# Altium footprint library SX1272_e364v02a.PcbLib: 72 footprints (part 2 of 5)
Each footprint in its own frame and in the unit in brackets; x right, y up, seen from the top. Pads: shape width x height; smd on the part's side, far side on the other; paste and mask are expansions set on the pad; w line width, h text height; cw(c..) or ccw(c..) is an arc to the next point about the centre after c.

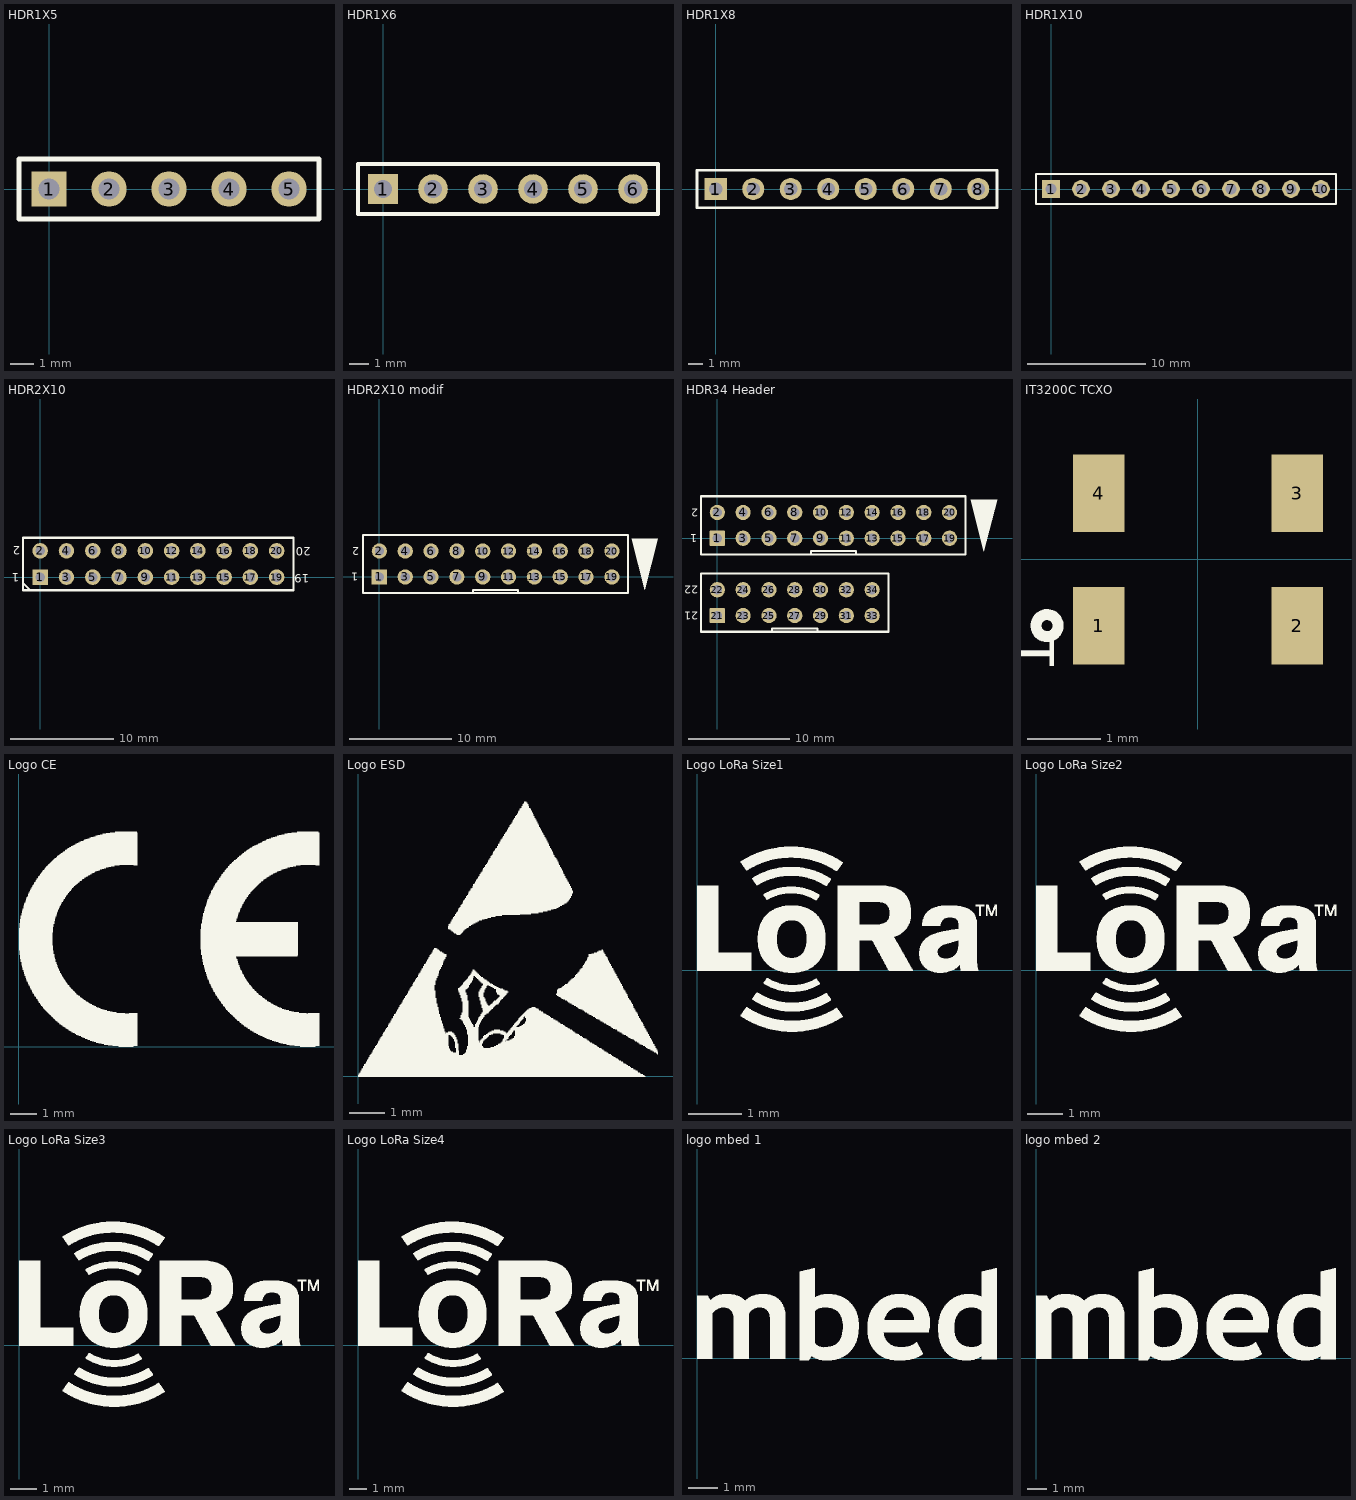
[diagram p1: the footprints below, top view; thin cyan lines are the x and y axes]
## HDR1X5 [mm] "Connector; Header; 5 Position"
pads (5):
  rect 1.5x1.5 hole 0.9: 1(0,0)
  round 1.5 hole 0.9: 2(2.54,0) 3(5.08,0) 4(7.62,0) 5(10.16,0)
Top Overlay:
  lines w0.2: -1.27,-1.27 -1.27,1.27 11.43,1.27 11.43,-1.27 -1.27,-1.27

## HDR1X6 [mm] "Connector; Header; 6 Position"
pads (6):
  rect 1.5x1.5 hole 0.9: 1(0,0)
  round 1.5 hole 0.9: 2(2.54,0) 3(5.08,0) 4(7.62,0) 5(10.16,0) 6(12.7,0)
Top Overlay:
  lines w0.2: -1.27,-1.27 -1.27,1.27 13.97,1.27 13.97,-1.27 -1.27,-1.27

## HDR1X8 [mm] "Connector; Header; 8 Position"
pads (8):
  rect 1.5x1.5 hole 0.9: 1(0,0)
  round 1.5 hole 0.9: 2(2.54,0) 3(5.08,0) 4(7.62,0) 5(10.16,0) 6(12.7,0) 7(15.24,0) 8(17.78,0)
Top Overlay:
  lines w0.2: -1.27,-1.27 19.05,-1.27 19.05,1.27 -1.27,1.27 -1.27,-1.27

## HDR1X10 [mm] "Connector; Header; 10 Position"
pads (10):
  rect 1.5x1.5 hole 0.9: 1(0,0)
  round 1.5 hole 0.9: 2(2.54,0) 3(5.08,0) 4(7.62,0) 5(10.16,0) 6(12.7,0) 7(15.24,0) 8(17.78,0) 9(20.32,0) 10(22.86,0)
Top Overlay:
  lines w0.2: -1.27,-1.27 24.13,-1.27 24.13,1.27 0.635,1.27 -1.27,1.27 -1.27,-1.27

## HDR2X10 [mm] "Connector; Header; 10x2 Position"
pads (20):
  rect 1.5x1.5 hole 0.9 paste+0 mask+0.1: 1(0,0)
  round 1.5 hole 0.9 paste+0 mask+0.1: 2(0,2.54) 3(2.54,0) 4(2.54,2.54) 5(5.08,0) 6(5.08,2.54) 7(7.62,0) 8(7.62,2.54) 9(10.16,0) 10(10.16,2.54) 11(12.7,0) 12(12.7,2.54) 13(15.24,0) 14(15.24,2.54) 15(17.78,0) 16(17.78,2.54) 17(20.32,0) 18(20.32,2.54) 19(22.86,0) 20(22.86,2.54)
Top Overlay:
  lines w0.2: -1.65,-0.6 -1.015,-1.235 ; -1.65,-1.27 0.635,-1.27 24.5,-1.27 24.5,3.81 0.635,3.81 -1.65,3.81 -1.65,-1.27
  text "20" at 26.15,2.9 h0.8
  text "19" at 26,0.3 h0.8
  text "1" at -2.05,0.4 h0.8
  text "2" at -1.95,3 h0.8

## HDR2X10 modif [mm] "Connector; Header; 10x2 Position - modified"
pads (20):
  rect 1.5x1.5 hole 0.9: 1(0,0)
  round 1.5 hole 0.9: 2(0,2.54) 3(2.54,0) 4(2.54,2.54) 5(5.08,0) 6(5.08,2.54) 7(7.62,0) 8(7.62,2.54) 9(10.16,0) 10(10.16,2.54) 11(12.7,0) 12(12.7,2.54) 13(15.24,0) 14(15.24,2.54) 15(17.78,0) 16(17.78,2.54) 17(20.32,0) 18(20.32,2.54) 19(22.86,0) 20(22.86,2.54)
Top Overlay:
  region: 26.107,-1.275 27.394,3.775 24.82,3.775
  lines w0.2: 9.207,-1.587 9.207,-1.27 13.335,-1.27 13.652,-1.27 13.652,-1.587 ; -1.587,-1.587 -1.587,4.127 24.447,4.127 24.447,-1.587 -1.587,-1.587
  text "1" at -2.1,0.4 h0.8
  text "2" at -2,2.9 h0.8

## HDR34 Header [mm] "Connector; Header; 34 Position - SM12xx Header"
pads (34):
  rrect10% 1.5x1.5 hole 0.9 mask+0.05: 1(0,0) 21(0,-7.62)
  round 1.5 hole 0.9 mask+0.05: 2(0,2.54) 3(2.54,0) 4(2.54,2.54) 5(5.08,0) 6(5.08,2.54) 7(7.62,0) 8(7.62,2.54) 9(10.16,0) 10(10.16,2.54) 11(12.7,0) 12(12.7,2.54) 13(15.24,0) 14(15.24,2.54) 15(17.78,0) 16(17.78,2.54) 17(20.32,0) 18(20.32,2.54) 19(22.86,0) 20(22.86,2.54) 22(0,-5.08) 23(2.54,-7.62) 24(2.54,-5.08) 25(5.08,-7.62) 26(5.08,-5.08) 27(7.62,-7.62) 28(7.62,-5.08) 29(10.16,-7.62) 30(10.16,-5.08) 31(12.7,-7.62) 32(12.7,-5.08) 33(15.24,-7.62) 34(15.24,-5.08)
Top Overlay:
  region: 26.243,-1.275 27.53,3.775 24.956,3.775
  lines w0.2: 5.397,-9.207 5.397,-8.89 9.525,-8.89 9.842,-8.89 9.842,-9.207 ; 9.207,-1.587 9.207,-1.27 13.335,-1.27 13.652,-1.27 13.652,-1.587 ; -1.587,-9.207 -1.587,-3.492 16.828,-3.492 16.828,-9.207 -1.587,-9.207 ; -1.587,-1.587 24.447,-1.587 24.447,4.127 -1.587,4.127 -1.587,-1.587
  text "2" at -1.9,2.9 h0.8
  text "1" at -2,0.4 h0.8
  text "21" at -1.9,-7.25 h0.8
  text "22" at -1.9,-4.7 h0.8

## IT3200C TCXO [mm] "SMD 3.2x2.5mm for IT3200C TCXO"
height 1
pads (4):
  rect 0.7x1.05 smd mask+0.05: 1(-1.35,-0.9) 2(1.35,-0.9) 3(1.35,0.9) 4(-1.35,0.9)
Top Overlay:
  circle w0.15: c-2.05,-0.9 r0.15
  text "1" at -1.95,-1.55 h0.6
3D body: height 1, standoff 0, extent -1.6,-1.25 1.6,1.25

## Logo CE [mm] "Logo CE"
height 0.1
Top Overlay:
  drawing of 654 lines, arcs and shapes, not listed

## Logo ESD [mm] "Logo ESD"
height 0.1
Top Overlay:
  drawing of 682 lines, arcs and shapes, not listed

## Logo LoRa Size1 [mm] "Logo LoRa Size1 - Top Overlay"
Top Overlay:
  drawing of 2375 lines, arcs and shapes, not listed

## Logo LoRa Size2 [mm] "Logo LoRa Size2 - Top Overlay"
Top Overlay:
  drawing of 2374 lines, arcs and shapes, not listed

## Logo LoRa Size3 [mm] "Logo LoRa Size3 - Top Overlay"
Top Overlay:
  drawing of 2375 lines, arcs and shapes, not listed

## Logo LoRa Size4 [mm] "Logo LoRa Size4 - Top Overlay"
Top Overlay:
  drawing of 2375 lines, arcs and shapes, not listed

## logo mbed 1 [mm] "logo mbed 1"
height 0.2
Top Overlay:
  drawing of 1792 lines, arcs and shapes, not listed

## logo mbed 2 [mm] "logo mbed 2"
height 0.2
Top Overlay:
  drawing of 1792 lines, arcs and shapes, not listed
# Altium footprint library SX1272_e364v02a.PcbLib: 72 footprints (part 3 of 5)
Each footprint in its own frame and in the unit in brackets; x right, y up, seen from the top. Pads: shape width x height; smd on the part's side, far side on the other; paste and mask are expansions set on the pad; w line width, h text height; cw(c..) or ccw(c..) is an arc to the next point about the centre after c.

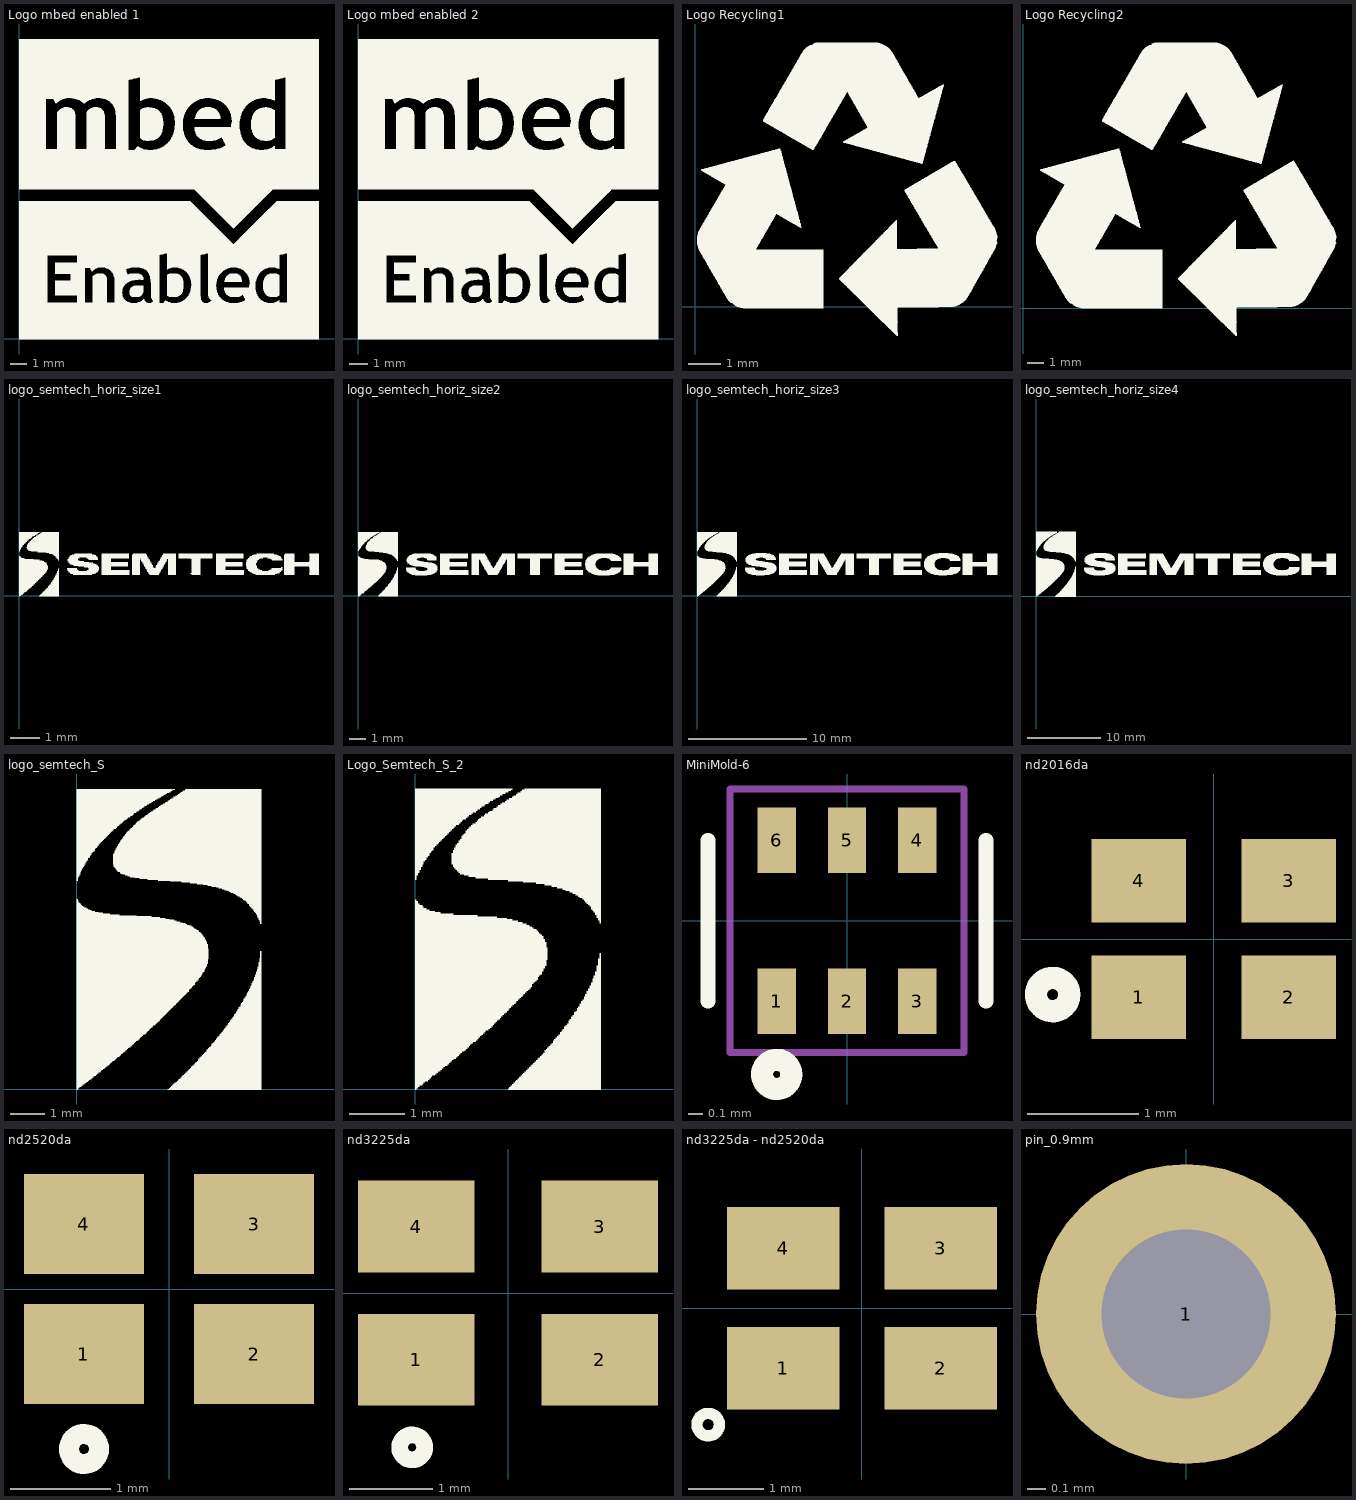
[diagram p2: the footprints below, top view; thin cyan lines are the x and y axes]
## Logo mbed enabled 1 [mm] "Logo mbed enabled 1"
height 0.2
Top Overlay:
  drawing of 3679 lines, arcs and shapes, not listed

## Logo mbed enabled 2 [mm] "Logo mbed enabled 2"
Top Overlay:
  drawing of 3679 lines, arcs and shapes, not listed

## Logo Recycling1 [mm] "Logo Recycling1"
height 0.1
Top Overlay:
  drawing of 3302 lines, arcs and shapes, not listed

## Logo Recycling2 [mm] "Logo Recycling2"
height 0.1
Top Overlay:
  drawing of 3309 lines, arcs and shapes, not listed

## logo_semtech_horiz_size1 [mm] "Logo semtech horizontal - size1 - S"
Top Overlay:
  drawing of 453 lines, arcs and shapes, not listed

## logo_semtech_horiz_size2 [mm] "Logo semtech horizontal - size2 - M"
Top Overlay:
  drawing of 790 lines, arcs and shapes, not listed

## logo_semtech_horiz_size3 [mm] "Logo semtech horizontal - size3 - L"
Top Overlay:
  drawing of 1137 lines, arcs and shapes, not listed

## logo_semtech_horiz_size4 [mm] "Logo semtech horizontal - size4 - XL"
Top Overlay:
  drawing of 1852 lines, arcs and shapes, not listed

## logo_semtech_S [mm] "Logo semtech S size4 - XL"
Top Overlay:
  drawing of 642 lines, arcs and shapes, not listed

## Logo_Semtech_S_2 [mm] "Logo semtech S - size2"
Top Overlay:
  drawing of 393 lines, arcs and shapes, not listed

## MiniMold-6 [mm] "MiniMold-6 Package 1.5x1.1mm"
height 0.55
pads (6):
  rect 0.26x0.45 smd mask+0.05: 1(-0.48,-0.55) 2(0,-0.55) 3(0.48,-0.55) 4(0.48,0.55) 5(0,0.55) 6(-0.48,0.55)
Top Overlay:
  circle w0.15: c-0.48,-1.05 r0.1
  lines w0.1: -0.95,-0.55 -0.95,0.55 ; 0.95,-0.55 0.95,0.55
Mechanical 15:
  lines w0.05: -0.8,-0.9 0.8,-0.9 0.8,0.9 -0.8,0.9 -0.8,-0.9
3D body: height 1, standoff 0, extent -0.75,-0.55 0.75,0.55

## nd2016da [mm] "Crystal SMD 2.0x1.6mm"
height 0.55
pads (4):
  rect 0.85x0.75 smd mask+0.05: 1(-0.675,-0.525) 2(0.675,-0.525) 3(0.675,0.525) 4(-0.675,0.525)
Top Overlay:
  circle w0.2: c-1.45,-0.5 r0.15
3D body: height 1, standoff 0, extent -1,-0.8 1,0.8

## nd2520da [mm] "Crystal SMD 2.5x2.0mm"
height 0.7
pads (4):
  rect 1.2x1 smd mask+0.05: 1(-0.85,-0.65) 2(0.85,-0.65) 3(0.85,0.65) 4(-0.85,0.65)
Top Overlay:
  circle w0.2: c-0.85,-1.6 r0.15
3D body: height 1, standoff 0, extent -1.25,-1 1.25,1

## nd3225da [mm] "Crystal SMD 3.2x2.5mm"
height 0.8
pads (4):
  rect 1.4x1.1 smd mask+0.05: 1(-1.1,-0.8) 2(1.1,-0.8) 3(1.1,0.8) 4(-1.1,0.8)
Top Overlay:
  circle w0.2: c-1.15,-1.85 r0.15
3D body: height 1, standoff 0, extent -1.6,-1.25 1.6,1.25

## nd3225da - nd2520da [mm] "Crystal SMD 3.2x2.5mm compatible with 2.5x2.0mm"
height 0.8
pads (4):
  rect 1.5x1.1 smd mask+0.05: 1(-1.05,-0.8) 2(1.05,-0.8) 3(1.05,0.8) 4(-1.05,0.8)
Top Overlay:
  circle w0.15: c-2.05,-1.55 r0.15
3D body: height 1, standoff 0, extent -1.6,-1.25 1.6,1.25

## pin_0.9mm [mm] "Generic Pin 0.9mm; 1 Lead"
height 1
pads (1):
  round 1.6 hole 0.9 mask+0.05: 1(0,0)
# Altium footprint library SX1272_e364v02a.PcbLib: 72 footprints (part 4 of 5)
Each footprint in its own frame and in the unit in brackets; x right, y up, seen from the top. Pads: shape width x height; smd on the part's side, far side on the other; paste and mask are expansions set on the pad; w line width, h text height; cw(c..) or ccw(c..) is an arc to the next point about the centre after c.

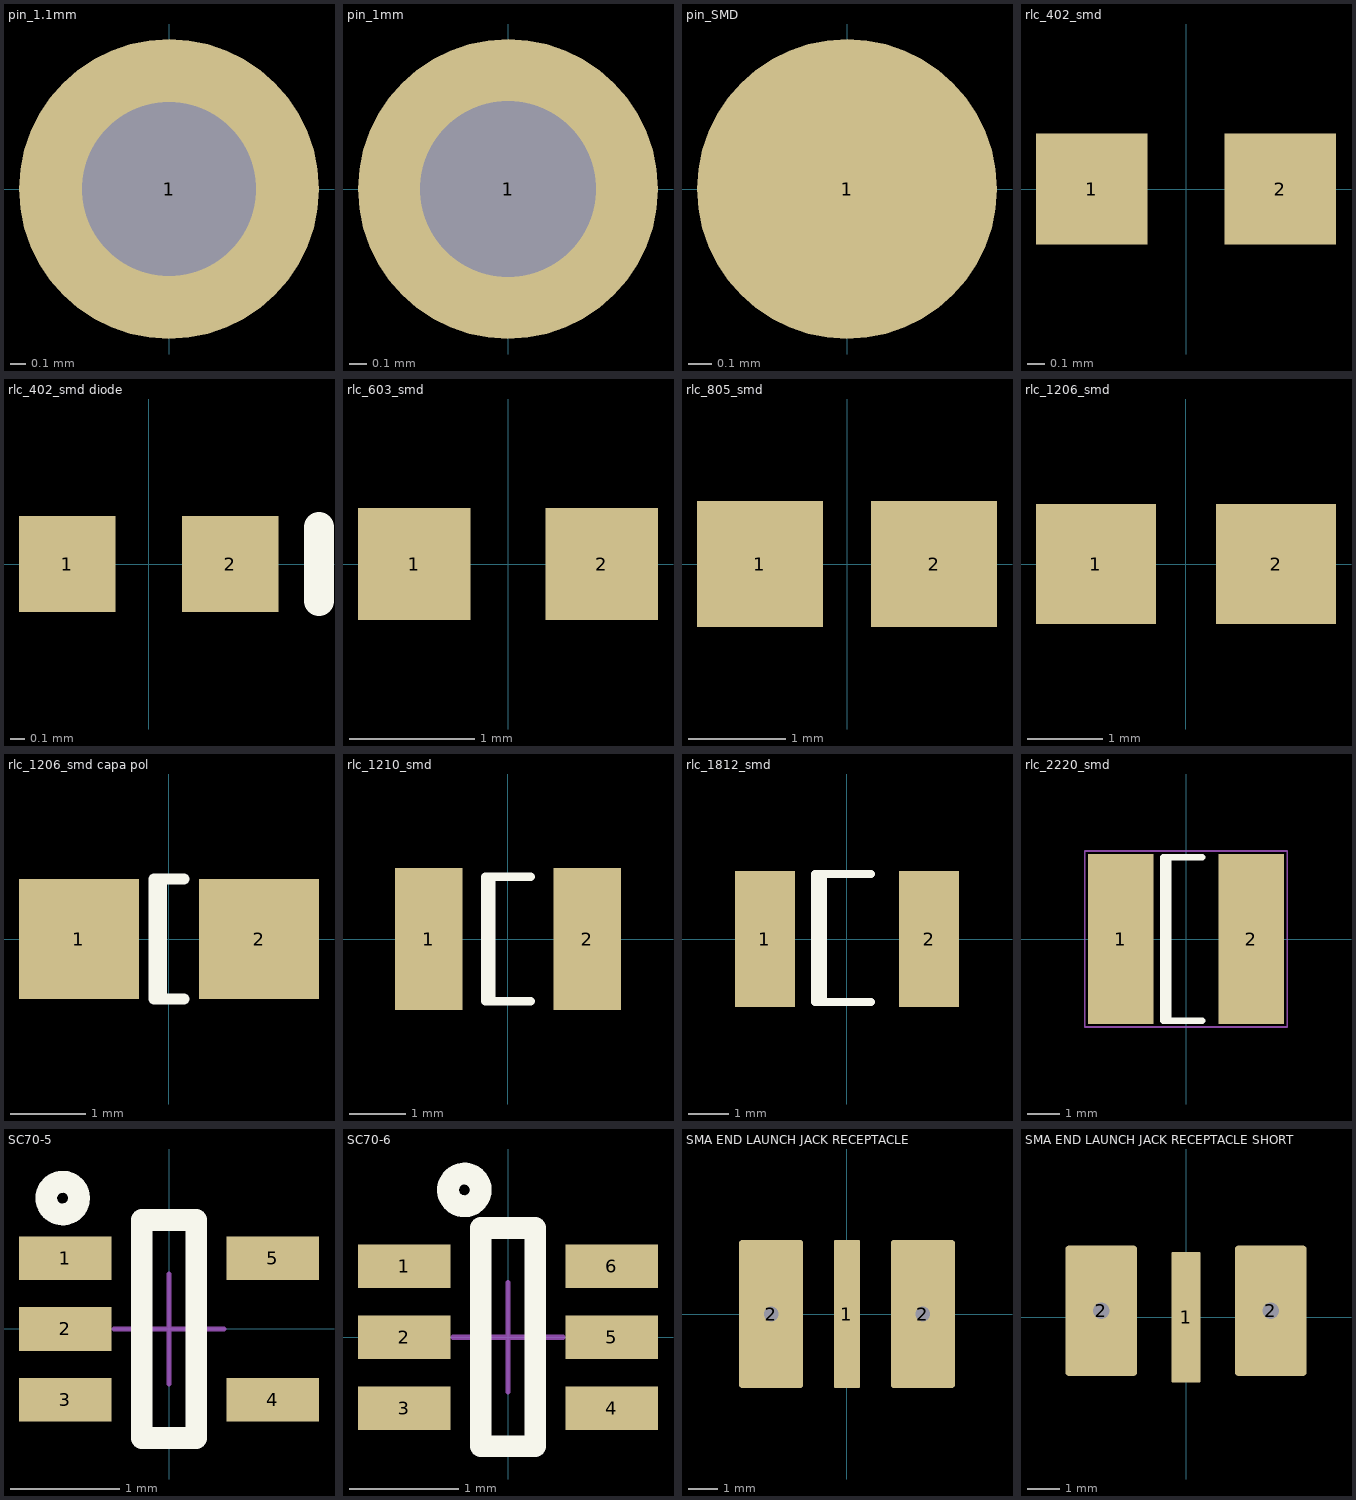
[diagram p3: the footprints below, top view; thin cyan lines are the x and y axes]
## pin_1.1mm [mm] "Generic Pin 1.1mm; 1 Lead"
height 1
pads (1):
  round 1.9 hole 1.1 mask+0.05: 1(0,0)

## pin_1mm [mm] "Generic Pin 1.1mm; 1 Lead"
height 1
pads (1):
  round 1.7 hole 1 paste+0 mask+0.05: 1(0,0)

## pin_SMD [mm] "Generic Pin; 1 pin SMD"
height 0.5
pads (1):
  round 1.27 smd paste-1 mask+0.05: 1(0,0)

## rlc_402_smd [mm] "Chip SMD component 402; Body 1.0 x 0.5 mm (LxW typ)"
height 0.8
pads (2):
  rect 0.65x0.65 smd mask+0.05: 1(-0.55,0) 2(0.55,0)

## rlc_402_smd diode [mm] "Chip SMD component 402; Body 1.0 x 0.5 mm (LxW typ)"
height 0.8
pads (2):
  rect 0.65x0.65 smd mask+0.05: 1(-0.55,0) 2(0.55,0)
Top Overlay:
  lines w0.2: 1.15,-0.25 1.15,0.25

## rlc_603_smd [mm] "Chip SMD component 603; Body 1.6 x 0.8mm (LxW typ)"
height 1
pads (2):
  rect 0.9x0.9 smd paste+0 mask+0.05: 1(-0.75,0) 2(0.75,0)

## rlc_805_smd [mm] "Chip SMD component 805; Body 2.0 x 1.25 mm (LxW typ)"
height 1.4
pads (2):
  rect 1.3x1.3 smd mask+0.05: 1(-0.9,0) 2(0.9,0)

## rlc_1206_smd [mm] "Chip SMD component 1206; Body 3.2 x 1.6 mm (LxW typ)"
height 2
pads (2):
  rect 1.6x1.6 smd mask+0.05: 1(-1.2,0) 2(1.2,0)

## rlc_1206_smd capa pol [mm] "Chip SMD component 1206; Body 3.2 x 1.6 mm (LxW typ)"
height 2
pads (2):
  rect 1.6x1.6 smd mask+0.05: 1(-1.2,0) 2(1.2,0)
Top Overlay:
  lines w0.15: -0.1,-0.8 -0.1,0.8 ; 0.2,-0.8 -0.2,-0.8 -0.2,0.8 0.2,0.8

## rlc_1210_smd [mm] "Chip SMD component 1210; Body 3.2 x 2.5 mm (LxW typ)"
height 2
pads (2):
  rect 1.2x2.5 smd mask+0.05: 1(-1.4,0) 2(1.4,0)
Top Overlay:
  lines w0.15: -0.3,-1.1 -0.3,1.1 ; 0.4,-1.1 -0.4,-1.1 -0.4,1.1 0.4,1.1

## rlc_1812_smd [mm] "Chip SMD component 1812; Body 4.5 x 3.2 mm (LxW typ)"
height 2.5
pads (2):
  rect 1.5x3.4 smd mask+0.05: 1(-2.05,0) 2(2.05,0)
Top Overlay:
  lines w0.2: -0.606,-1.579 -0.606,1.621 ; 0.604,-1.579 -0.796,-1.579 -0.796,1.621 0.604,1.621

## rlc_2220_smd [mm] "Chip SMD component ; Body 5.7 x 5.0 mm (LxW typ)"
height 5
pads (2):
  rect 2x5.2 smd mask+0.05: 1(-2,0) 2(2,0)
Top Overlay:
  lines w0.2: -0.55,-2.5 -0.55,2.5 ; 0.5,-2.5 -0.7,-2.5 -0.7,2.5 0.5,2.5
Mechanical 15:
  lines w0.05: -3.1,-2.7 3.1,-2.7 3.1,2.7 -3.1,2.7 -3.1,-2.7

## SC70-5 [mm] "SC70 5-Leads, Body 2.0x1.25mm, Pitch 0.65mm"
height 1.45
pads (5):
  rect 0.85x0.4 smd mask+0.05: 1(-0.95,0.65) 2(-0.95,0) 3(-0.95,-0.65) 4(0.95,-0.65) 5(0.95,0.65)
Top Overlay:
  circle w0.2: c-0.975,1.2 r0.15
  lines w0.2: -0.25,-1 0.25,-1 0.25,1 -0.25,1 -0.25,-1
Mechanical 15:
  lines w0.05: -0.5,0 0.5,0 ; 0,-0.5 0,0.5
3D body: height 1.45, standoff 0, extent -0.625,-1 0.625,1

## SC70-6 [mm] "SC70 6-Leads, Body 2.0x1.25mm, Pitch 0.65mm"
height 1.45
pads (6):
  rect 0.85x0.4 smd mask+0.05: 1(-0.95,0.65) 2(-0.95,0) 3(-0.95,-0.65) 4(0.95,-0.65) 5(0.95,0) 6(0.95,0.65)
Top Overlay:
  circle w0.2: c-0.4,1.35 r0.15
  lines w0.2: -0.25,-1 0.25,-1 0.25,1 -0.25,1 -0.25,-1
Mechanical 15:
  lines w0.05: -0.5,0 0.5,0 ; 0,-0.5 0,0.5
3D body: height 1.45, standoff 0, extent -0.625,-1 0.625,1

## SMA END LAUNCH JACK RECEPTACLE [mm] "SMA Connector - End Launch Jack Receptacle"
height 8
pads (3):
  rrect10% 0.9x5.08 smd paste+0 mask+0.05: 1(0,0)
  rrect10% 2.2x5.08 hole 0.5 mask+0.05: 2(-2.6,0) 2(2.6,0)

## SMA END LAUNCH JACK RECEPTACLE SHORT [mm] "SMA Connector - End Launch Jack Receptacle - Short"
height 8
pads (3):
  rrect10% 0.9x4 smd paste+0 mask+0.05: 1(0,0)
  rrect10% 2.2x4 hole 0.5 mask+0.05: 2(-2.6,0.2) 2(2.6,0.2)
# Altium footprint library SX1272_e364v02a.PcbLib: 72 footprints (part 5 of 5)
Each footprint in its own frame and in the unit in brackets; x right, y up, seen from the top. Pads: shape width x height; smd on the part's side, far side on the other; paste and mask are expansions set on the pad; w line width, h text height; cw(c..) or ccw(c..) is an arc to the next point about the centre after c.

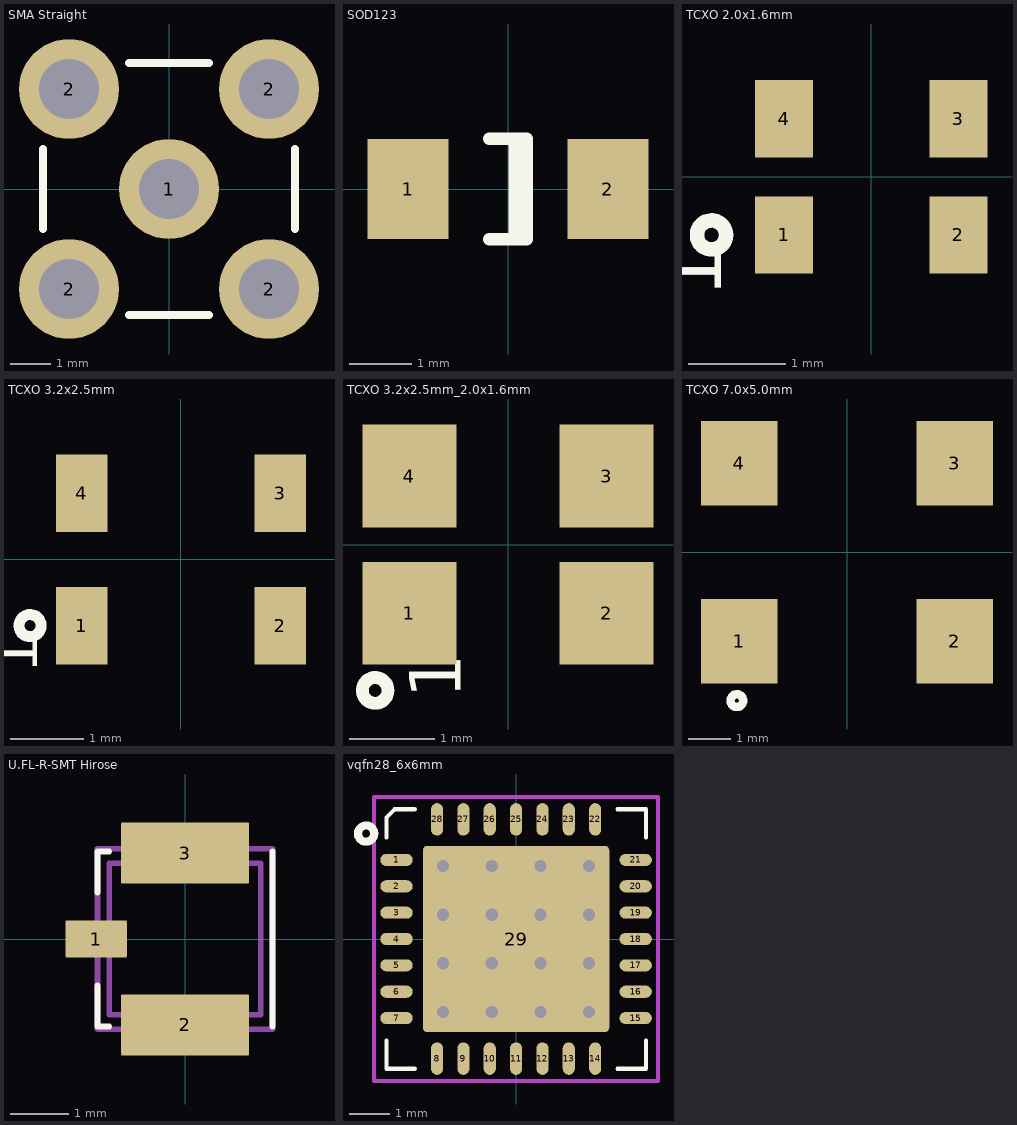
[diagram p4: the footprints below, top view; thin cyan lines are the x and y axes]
## SMA Straight [mm] "SMA Connector; Straight"
height 10
pads (5):
  round 2.5 hole 1.5 paste+0 mask+0.1: 1(0,0) 2(-2.5,-2.5) 2(-2.5,2.5) 2(2.5,-2.5) 2(2.5,2.5)
Top Overlay:
  lines w0.2: -3.15,-1 -3.15,1 ; -1,-3.15 1,-3.15 ; -1,3.15 1,3.15 ; 3.15,-1 3.15,1
Mechanical 1:
  circle w0.025: c0,0 r0.2

## SOD123 [mm] "SOD123; Chip Diode; Body  2.7 x 1.6 mm (LxW typ)"
height 1.35
pads (2):
  rect 1.3x1.6 smd mask+0.05: 1(-1.6,0) 2(1.6,0)
Top Overlay:
  lines w0.2: -0.3,-0.8 0.3,-0.8 0.3,0.8 -0.3,0.8 ; 0.11,-0.8 0.11,0.8

## TCXO 2.0x1.6mm [mm] "SMD 2.0x1.6mm for TCXO or VCTCXO"
height 1
pads (4):
  rect 0.6x0.8 smd mask+0.05: 1(-0.9,-0.6) 2(0.9,-0.6) 3(0.9,0.6) 4(-0.9,0.6)
Top Overlay:
  circle w0.15: c-1.65,-0.6 r0.15
  text "1" at -1.55,-1.25 h0.6
3D body: height 1, standoff 0, extent -1,-0.8 1,0.8

## TCXO 3.2x2.5mm [mm] "SMD 3.2x2.5mm for TCXO or VCTCXO"
height 1
pads (4):
  rect 0.7x1.05 smd mask+0.05: 1(-1.35,-0.9) 2(1.35,-0.9) 3(1.35,0.9) 4(-1.35,0.9)
Top Overlay:
  circle w0.15: c-2.05,-0.9 r0.15
  text "1" at -1.95,-1.55 h0.6
3D body: height 1, standoff 0, extent -1.6,-1.25 1.6,1.25

## TCXO 3.2x2.5mm_2.0x1.6mm [mm] "SMD 3.2x2.5mm & 2.0x1.6mm compatible for TCXO or VCTCXO"
height 1
pads (4):
  rect 1.1x1.2 smd mask+0.05: 1(-1.15,-0.8) 2(1.15,-0.8) 3(1.15,0.8) 4(-1.15,0.8)
Top Overlay:
  circle w0.15: c-1.55,-1.7 r0.15
  text "1" at -0.55,-1.8 h0.6
3D body: height 1, standoff 0, extent -1.6,-1.25 1.6,1.25

## TCXO 7.0x5.0mm [mm] "VTCXO SMD 7.0x5.0mm"
height 1
pads (4):
  rect 1.8x2 smd mask+0.05: 1(-2.54,-2.1) 2(2.54,-2.1) 3(2.54,2.1) 4(-2.54,2.1)
Top Overlay:
  circle w0.2: c-2.6,-3.5 r0.15
3D body: height 1, standoff 0, extent -3.5,-2.5 3.5,2.5

## U.FL-R-SMT Hirose [mm] "Hirose U.FL RF receptacle - U.FL-R-SMT"
height 1.2
pads (3):
  rrect5% 1.05x0.635 smd: 1(-1.525,0)
  rrect5% 2.2x1.05 smd: 2(0,-1.475) 3(0,1.475)
Top Overlay:
  lines w0.1: -1.5,-0.8 -1.5,-1.5 -1.3,-1.5 ; -1.5,0.8 -1.5,1.5 -1.3,1.5 ; 1.5,-1.5 1.5,1.5
Mechanical 13:
  lines w0.1: -1.5,-1.55 1.5,-1.55 1.5,1.55 -1.5,1.55 -1.5,-1.55
Mechanical 15:
  lines w0.1: -1.3,-1.3 1.3,-1.3 1.3,1.3 -1.3,1.3 -1.3,-1.3
3D body: height 16, standoff 1.3, extent -1.5,-1.5 1.5,1.5

## vqfn28_6x6mm [mm] "28 Leads, Body 6.0x6.0mm, Pitch 0.65mm, VQFN28"
height 1
pads (29):
  oval 0.8x0.3 smd mask+0.05: 1(-2.95,1.95) 2(-2.95,1.3) 3(-2.95,0.65) 4(-2.95,0) 5(-2.95,-0.65) 6(-2.95,-1.3) 7(-2.95,-1.95) 15(2.95,-1.95) 16(2.95,-1.3) 17(2.95,-0.65) 18(2.95,0) 19(2.95,0.65) 20(2.95,1.3) 21(2.95,1.95)
  oval 0.3x0.8 smd mask+0.05: 8(-1.95,-2.95) 9(-1.3,-2.95) 10(-0.65,-2.95) 11(0,-2.95) 12(0.65,-2.95) 13(1.3,-2.95) 14(1.95,-2.95) 22(1.95,2.95) 23(1.3,2.95) 24(0.65,2.95) 25(0,2.95) 26(-0.65,2.95) 27(-1.3,2.95) 28(-1.95,2.95)
  rrect5% 4.6x4.6 smd paste-3.3 mask+0.05: 29(0,0)
via 0.6,-1.8 diameter 0.6 hole 0.3
via 1.8,-0.6 diameter 0.6 hole 0.3
via -1.8,1.8 diameter 0.6 hole 0.3
via -1.8,-0.6 diameter 0.6 hole 0.3
via -1.8,0.6 diameter 0.6 hole 0.3
via 0.6,-0.6 diameter 0.6 hole 0.3
via 1.8,-1.8 diameter 0.6 hole 0.3
via -0.6,-1.8 diameter 0.6 hole 0.3
via -1.8,-1.8 diameter 0.6 hole 0.3
via -0.6,1.8 diameter 0.6 hole 0.3
via -0.6,0.6 diameter 0.6 hole 0.3
via -0.6,-0.6 diameter 0.6 hole 0.3
via 0.6,0.6 diameter 0.6 hole 0.3
via 0.6,1.8 diameter 0.6 hole 0.3
via 1.8,1.8 diameter 0.6 hole 0.3
via 1.8,0.6 diameter 0.6 hole 0.3
Top Overlay:
  circle w0.2: c-3.7,2.6 r0.2
  lines w0.1: -3.2,-2.5 -3.2,-3.2 -2.5,-3.2 ; -3.2,2.5 -3.2,3 -3,3.2 -2.5,3.2 ; 2.5,-3.2 3.2,-3.2 3.2,-2.5 ; 2.5,3.2 3.2,3.2 3.2,2.5
Top Paste:
  region: -1.6,-0.8 -1.6,-1.6 -0.8,-1.6 -0.8,-0.8
  region: 0.8,-0.8 0.8,-1.6 1.6,-1.6 1.6,-0.8
  region: -0.4,-0.8 -0.4,-1.6 0.4,-1.6 0.4,-0.8
  region: 0.8,0.4 0.8,-0.4 1.6,-0.4 1.6,0.4
  region: -1.6,1.6 -1.6,0.8 -0.8,0.8 -0.8,1.6
  region: -0.4,1.6 -0.4,0.8 0.4,0.8 0.4,1.6
  region: -1.6,0.4 -1.6,-0.4 -0.8,-0.4 -0.8,0.4
  region: -0.4,0.4 -0.4,-0.4 0.4,-0.4 0.4,0.4
  region: 0.8,1.6 0.8,0.8 1.6,0.8 1.6,1.6
Mechanical 15 keep-out:
  lines w0.1: -3.5,-3.5 -3.5,3.5 3.5,3.5 3.5,-3.5 -3.5,-3.5
3D body: height 1, standoff 0.05, extent -3,-3 3,3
